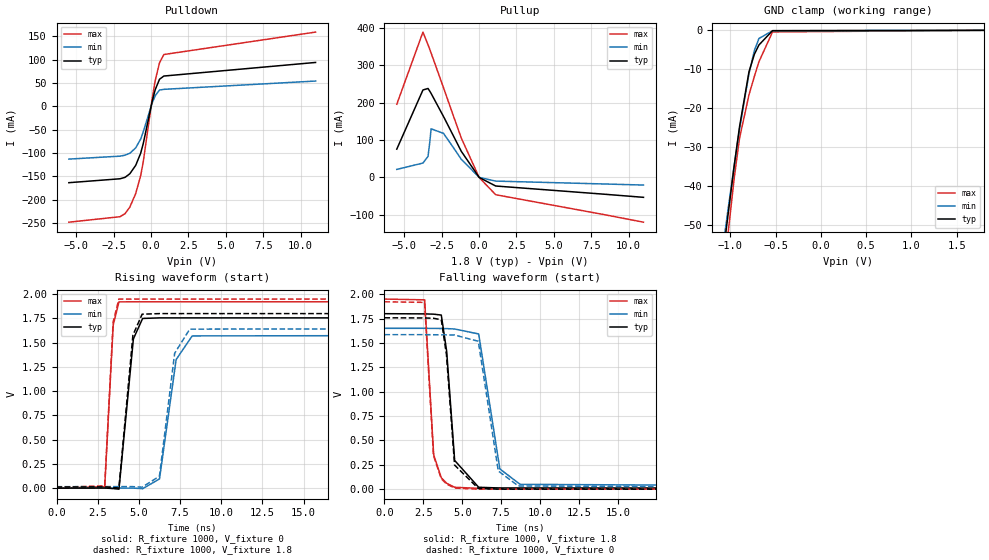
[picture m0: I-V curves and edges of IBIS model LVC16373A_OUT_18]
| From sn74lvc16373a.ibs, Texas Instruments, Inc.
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[Model]   LVC16373A_OUT_18
Model_type  3-state
Enable   Active-Low
Vref =   0
Rref =   1000
Cref =   30p
Vmeas =   0.9
| variable   typ   min   max
C_comp   5.28pF   4.71pF   6.10pF
| C_pullup   6.13pF   5.53pF   6.81pF
| C_pulldown   8.31pF   6.61pF   10.14pF
| C_tri-state   5.28pF   4.71pF   6.10pF
[Temperature Range]   40   100   -40
| Ambient temperature   25   85   -40
[Voltage range]   1.8   1.65   1.95
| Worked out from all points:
|   slope of the pulldown table from 0 to 0.27 V, typ, clamps not added: 7.65 ohm
|   slope of the pullup table from 0 to 0.27 V, typ, clamps not added: 27.4 ohm
|   GND clamp passes 1 mA (typ) near -0.60 V on its own axis
|   rising waveform, R_fixture 1000, V_fixture 0: 20-80 % time 380ps typ, 692ps min, 239ps max; typ from 0 V to 1.76 V
|   falling waveform, R_fixture 1000, V_fixture 1.8: 20-80 % time 481ps typ, 783ps min, 350ps max; typ from 1.8 V to 0.012 V
|   rising waveform, R_fixture 1000, V_fixture 1.8: 20-80 % time 366ps typ, 633ps min, 235ps max; typ from 0.012 V to 1.8 V
|   falling waveform, R_fixture 1000, V_fixture 0: 20-80 % time 467ps typ, 742ps min, 343ps max; typ from 1.76 V to 0 V
[GND Clamp]
| LVC16373A_OUT_18
|   Voltage   I(typ)   I(min)   I(max)
-5.5V     -1.092A    -985.9mA   -1.265A
-1.12V    -65.63mA   -62.5mA    -73.1mA
-1.09V    -59.68mA   -57.14mA   -66.23mA
-1.06V    -53.82mA   -51.86mA   -59.48mA
-1.045V   -50.92mA   -49.25mA   -56.15mA
-960mV    -35.13mA   -34.95mA   -38.34mA
-900mV    -24.87mA   -25.49mA   -27.8mA
-795mV    -10.66mA   -11.13mA   -16.59mA
-735mV    -6.119mA   -5.16mA    -11.82mA
-685mV    -3.765mA   -2.107mA   -8.076mA
-535mV    -84.46uA   -113.4uA   -414.9uA
1.8V      37.81pA    12.23nA    -1.85nA
[Pulldown]
| LVC16373A_OUT_18
|   Voltage   I(typ)   I(min)   I(max)
-5.5V     -163.6mA   -113mA     -248.3mA
-2.075V   -155.2mA   -106.7mA   -236.5mA
-1.745V   -152.2mA   -104.6mA   -230mA
-1.42V    -144.4mA   -100.5mA   -215.8mA
-1.03V    -126.4mA   -88.99mA   -186.9mA
-695mV    -100.2mA   -69.99mA   -148.2mA
-520mV    -79.1mA    -54.01mA   -118mA
70mV      10.47mA    6.993mA    15.91mA
275mV     35.8mA     23.13mA    55.48mA
565mV     58.22mA    35.03mA    93.73mA
855mV     65.08mA    36.56mA    111.2mA
11V       94.21mA    54.33mA    159.3mA
[Pullup]
| LVC16373A_OUT_18
|   Voltage   I(typ)   I(min)   I(max)
-5.5V     75.37mA    20.95mA    195.8mA
-3.75V    234.1mA    38.04mA    389.4mA
-3.41V    238.1mA    55.86mA    355.3mA
-3.285V   230.3mA    96.69mA    342mA
-3.205V   224.9mA    129.9mA    333.3mA
-2.375V   162.9mA    117.7mA    240.2mA
-1.61V    102.9mA    73.43mA    152.8mA
-1.185V   69.47mA    48.03mA    105.1mA
15mV      -631.9uA   -377.7uA   -1.037mA
1.115V    -23.53mA   -10.37mA   -46.86mA
8.41V     -45.64mA   -18.13mA   -100.6mA
11V       -53.91mA   -20.99mA   -120.6mA
[Ramp]
| LVC16373A_OUT_18
| variable   typ   min   max
dV/dt_r   1.06/3.92E-10   0.96/7.01E-10   1.16/2.51E-10
dV/dt_f   1.07/4.87E-10   0.98/7.88E-10   1.17/3.60E-10
R_load = 1000
[Rising Waveform]
| LVC16373A_OUT_18
R_fixture =   1000
C_fixture =   0
L_fixture =   0
V_fixture =   0
V_fixture_min = 0
V_fixture_max = 0
|   Time   V(typ)   V(min)   V(max)
0s        561.2pV    2.27nV     19.09nV
2.925ns   1.743mV    188.8uV    15.66mV
3.44ns    -3.94mV    1.332mV    1.683V
3.79ns    -10.17mV   824.7uV    1.921V
4.665ns   1.54V      696.2uV    1.922V
5.225ns   1.75V      -5.31mV    1.922V
6.25ns    1.756V     95.72mV    1.922V
7.26ns    1.756V     1.327V     1.922V
8.235ns   1.756V     1.57V      1.922V
50ns      1.756V     1.581V     1.922V
[Falling Waveform]
| LVC16373A_OUT_18
R_fixture =   1000
C_fixture =   0
L_fixture =   0
V_fixture =   1.8
V_fixture_min = 1.65
V_fixture_max = 1.95
|   Time   V(typ)   V(min)   V(max)
0s        1.8V       1.65V      1.95V
2.585ns   1.798V     1.65V      1.942V
3.165ns   1.795V     1.649V     353.4mV
3.655ns   1.786V     1.648V     117.7mV
4ns       1.416V     1.647V     60.59mV
4.515ns   294.8mV    1.643V     19.35mV
6.06ns    19.39mV    1.592V     8.507mV
7.42ns    11.92mV    207.4mV    8.37mV
8.725ns   11.61mV    49.58mV    8.362mV
50ns      11.53mV    15.73mV    8.262mV
[Rising Waveform]
| LVC16373A_OUT_18
R_fixture =   1000
C_fixture =   0
L_fixture =   0
V_fixture =   1.8
V_fixture_min = 1.65
V_fixture_max = 1.95
|   Time   V(typ)   V(min)   V(max)
0s        11.51mV    15.68mV    8.257mV
2.925ns   13.05mV    15.89mV    24.81mV
3.435ns   7.463mV    16.78mV    1.714V
3.785ns   1.792mV    16.11mV    1.95V
4.635ns   1.577V     15.89mV    1.95V
5.195ns   1.794V     10.37mV    1.95V
6.245ns   1.8V       123.5mV    1.95V
7.17ns    1.8V       1.392V     1.95V
8.085ns   1.8V       1.64V      1.95V
50ns      1.8V       1.65V      1.95V
[Falling Waveform]
| LVC16373A_OUT_18
R_fixture =   1000
C_fixture =   0
L_fixture =   0
V_fixture =   0
V_fixture_min = 0
V_fixture_max = 0
|   Time   V(typ)   V(min)   V(max)
0s        1.758V     1.585V     1.922V
2.58ns    1.756V     1.585V     1.916V
3.155ns   1.753V     1.584V     342.1mV
3.655ns   1.738V     1.583V     107.8mV
3.985ns   1.381V     1.583V     53.5mV
4.51ns    247.2mV    1.581V     11.1mV
6.035ns   7.702mV    1.517V     252uV
7.32ns    430.2uV    186.4mV    114.1uV
8.61ns    105.2uV    33.14mV    103.3uV
50ns      12.69uV    48.2uV     5.024uV
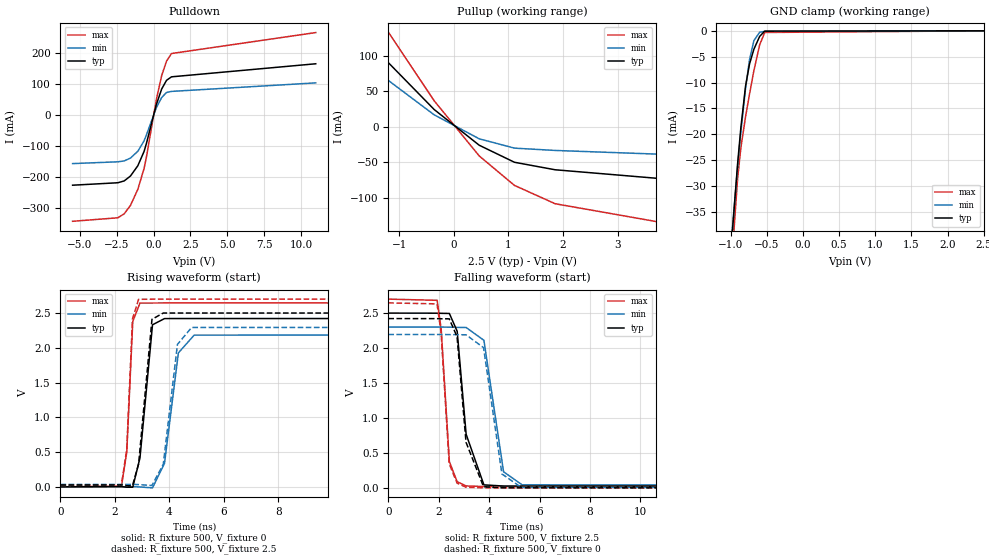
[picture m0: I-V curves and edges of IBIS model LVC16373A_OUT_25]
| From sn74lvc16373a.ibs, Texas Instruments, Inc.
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[Model]   LVC16373A_OUT_25
Model_type  3-state
Enable   Active-Low
Vref =   0
Rref =   500
Cref =   30p
Vmeas =   1.25
| variable   typ   min   max
C_comp   5.09pF   4.48pF   6.05pF
| C_pullup   6.01pF   5.36pF   6.86pF
| C_pulldown   7.61pF   6.27pF   8.94pF
| C_tri-state   5.09pF   4.48pF   6.05pF
[Temperature Range]   40   100   -40
| Ambient temperature   25   85   -40
[Voltage range]   2.5   2.3   2.7
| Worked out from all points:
|   slope of the pulldown table from 0 to 0.375 V, typ, clamps not added: 6 ohm
|   slope of the pullup table from 0 to 0.375 V, typ, clamps not added: 17.5 ohm
|   GND clamp passes 1 mA (typ) near -0.60 V on its own axis
|   rising waveform, R_fixture 500, V_fixture 0: 20-80 % time 256ps typ, 373ps min, 165ps max; typ from 0 V to 2.42 V
|   falling waveform, R_fixture 500, V_fixture 2.5: 20-80 % time 333ps typ, 469ps min, 250ps max; typ from 2.5 V to 0.025 V
|   rising waveform, R_fixture 500, V_fixture 2.5: 20-80 % time 254ps typ, 356ps min, 162ps max; typ from 0.025 V to 2.5 V
|   falling waveform, R_fixture 500, V_fixture 0: 20-80 % time 321ps typ, 441ps min, 244ps max; typ from 2.42 V to 0 V
[GND Clamp]
| LVC16373A_OUT_25
|   Voltage   I(typ)   I(min)   I(max)
-5.5V     -1.092A    -985.9mA   -1.265A
-1.115V   -64.63mA   -61.6mA    -71.95mA
-1.085V   -58.69mA   -56.25mA   -65.09mA
-1.055V   -52.85mA   -50.99mA   -58.36mA
-905mV    -25.68mA   -26.25mA   -28.57mA
-860mV    -18.71mA   -19.61mA   -22.6mA
-795mV    -10.66mA   -11.13mA   -16.59mA
-740mV    -6.406mA   -5.567mA   -12.21mA
-680mV    -3.568mA   -1.9mA     -7.713mA
-600mV    -1.079mA   -275.4uA   -2.703mA
-530mV    -59.09uA   -106.9uA   -320.1uA
2.5V      50.35pA    32nA       -2.079nA
[Pulldown]
| LVC16373A_OUT_25
|   Voltage   I(typ)   I(min)   I(max)
-5.5V     -227.2mA   -157.4mA   -343.8mA
-2.435V   -219.3mA   -151.6mA   -332.5mA
-2V       -213.4mA   -148.8mA   -319.6mA
-1.575V   -197.6mA   -139.6mA   -292.6mA
-1.075V   -164.4mA   -117.7mA   -240.6mA
-650mV    -118.1mA   -83.84mA   -173.1mA
-495mV    -93.12mA   -65.26mA   -137.4mA
185mV     33.61mA    23.27mA    50.14mA
545mV     83.64mA    56.25mA    127.2mA
875mV     111.7mA    72.29mA    173.9mA
1.21V     122.9mA    75.8mA     198.2mA
11V       165.1mA    103.4mA    265.9mA
[Pullup]
| LVC16373A_OUT_25
|   Voltage   I(typ)   I(min)   I(max)
-5.5V     443.1mA    133.6mA    676.2mA
-5.3V     442mA      146.1mA    654.8mA
-2.67V    223.9mA    166.9mA    324.6mA
-2.115V   173mA      128.2mA    251.7mA
-1.69V    134.3mA    98.74mA    196.2mA
-1.285V   97.35mA    70.47mA    143.5mA
-360mV    24.51mA    17.05mA    36.8mA
465mV     -25.84mA   -16.77mA   -40.96mA
1.11V     -49.84mA   -29.91mA   -82.48mA
1.855V    -60.43mA   -33.17mA   -108.3mA
4.49V     -77.42mA   -40.47mA   -144.1mA
11V       -121.1mA   -58.83mA   -239.8mA
[Ramp]
| LVC16373A_OUT_25
| variable   typ   min   max
dV/dt_r   1.46/2.66E-10   1.32/3.80E-10   1.60/1.70E-10
dV/dt_f   1.49/3.41E-10   1.36/4.74E-10   1.61/2.54E-10
R_load = 500
[Rising Waveform]
| LVC16373A_OUT_25
R_fixture =   500
C_fixture =   0
L_fixture =   0
V_fixture =   0
V_fixture_min = 0
V_fixture_max = 0
|   Time   V(typ)   V(min)   V(max)
0s        617.4pV    1.958nV    18.26nV
2.24ns    2.519mV    383.6uV    8.954mV
2.435ns   -6.245mV   2.016mV    499.9mV
2.655ns   -5.407mV   2.679mV    2.378V
2.92ns    416.1mV    -2.426mV   2.644V
3.38ns    2.331V     -15.13mV   2.644V
3.82ns    2.42V      337mV      2.645V
4.33ns    2.421V     1.927V     2.645V
4.91ns    2.421V     2.182V     2.645V
50ns      2.421V     2.191V     2.645V
[Falling Waveform]
| LVC16373A_OUT_25
R_fixture =   500
C_fixture =   0
L_fixture =   0
V_fixture =   2.5
V_fixture_min = 2.3
V_fixture_max = 2.7
|   Time   V(typ)   V(min)   V(max)
0s        2.5V       2.3V       2.7V
1.935ns   2.499V     2.3V       2.683V
2.095ns   2.497V     2.3V       2.269V
2.42ns    2.495V     2.299V     374.2mV
2.73ns    2.24V      2.296V     87.5mV
3.085ns   766.4mV    2.294V     27.43mV
3.79ns    42.52mV    2.111V     19.07mV
4.57ns    26.27mV    230.1mV    18.74mV
5.305ns   25.66mV    43.14mV    18.68mV
50ns      25.46mV    33.49mV    18.58mV
[Rising Waveform]
| LVC16373A_OUT_25
R_fixture =   500
C_fixture =   0
L_fixture =   0
V_fixture =   2.5
V_fixture_min = 2.3
V_fixture_max = 2.7
|   Time   V(typ)   V(min)   V(max)
0s        25.45mV    33.45mV    18.57mV
2.24ns    27.69mV    33.83mV    28.34mV
2.435ns   18.91mV    35.28mV    543.1mV
2.645ns   17.43mV    35.61mV    2.416V
2.87ns    328.7mV    31.4mV     2.697V
3.36ns    2.41V      19.15mV    2.699V
3.775ns   2.5V       324.7mV    2.7V
4.295ns   2.5V       2.048V     2.7V
4.815ns   2.5V       2.292V     2.7V
50ns      2.5V       2.3V       2.7V
[Falling Waveform]
| LVC16373A_OUT_25
R_fixture =   500
C_fixture =   0
L_fixture =   0
V_fixture =   0
V_fixture_min = 0
V_fixture_max = 0
|   Time   V(typ)   V(min)   V(max)
0s        2.422V     2.194V     2.646V
1.93ns    2.421V     2.194V     2.632V
2.09ns    2.419V     2.194V     2.23V
2.415ns   2.418V     2.192V     342.2mV
2.725ns   2.162V     2.191V     67.56mV
3.08ns    652.7mV    2.19V      8.625mV
3.775ns   16.27mV    2.006V     485.8uV
4.505ns   810.4uV    198.7mV    178.5uV
5.265ns   206.8uV    8.456mV    105.8uV
50ns      9.942uV    37.37uV    3.898uV
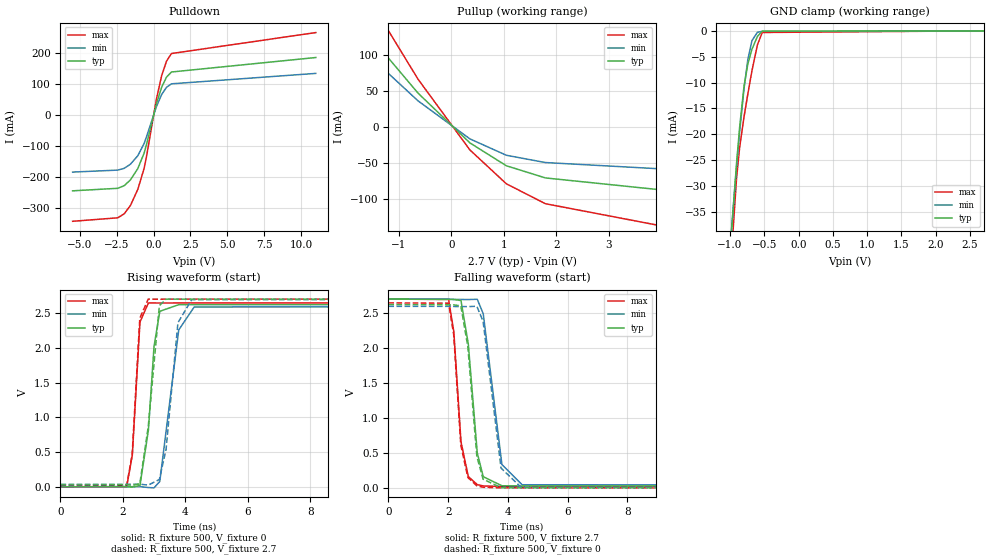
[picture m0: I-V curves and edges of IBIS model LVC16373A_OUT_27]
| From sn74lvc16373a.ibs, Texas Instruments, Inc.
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[Model]   LVC16373A_OUT_27
Model_type  3-state
Enable   Active-Low
Vref =   0
Rref =   500
Cref =   50p
Vmeas =   1.5
| variable   typ   min   max
C_comp   5.04pF   4.40pF   6.03pF
| C_pullup   5.98pF   5.29pF   6.85pF
| C_pulldown   7.47pF   6.10pF   8.69pF
| C_tri-state   5.04pF   4.40pF   6.03pF
[Temperature Range]   40   100   -40
| Ambient temperature   25   85   -40
[Voltage range]   2.7   2.7   2.7
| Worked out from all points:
|   slope of the pulldown table from 0 to 0.405 V, typ, clamps not added: 5.72 ohm
|   slope of the pullup table from 0 to 0.405 V, typ, clamps not added: 16.1 ohm
|   GND clamp passes 1 mA (typ) near -0.60 V on its own axis
|   rising waveform, R_fixture 500, V_fixture 0: 20-80 % time 245ps typ, 318ps min, 183ps max; typ from 0 V to 2.62 V
|   falling waveform, R_fixture 500, V_fixture 2.7: 20-80 % time 311ps typ, 396ps min, 247ps max; typ from 2.7 V to 0.026 V
|   rising waveform, R_fixture 500, V_fixture 2.7: 20-80 % time 238ps typ, 307ps min, 180ps max; typ from 0.026 V to 2.7 V
|   falling waveform, R_fixture 500, V_fixture 0: 20-80 % time 300ps typ, 376ps min, 242ps max; typ from 2.62 V to 0 V
[GND Clamp]
| LVC16373A_OUT_27
|   Voltage   I(typ)   I(min)   I(max)
-5.5V     -1.092A    -985.9mA   -1.265A
-1.115V   -64.63mA   -61.6mA    -71.95mA
-1.085V   -58.69mA   -56.25mA   -65.09mA
-1.055V   -52.85mA   -50.99mA   -58.36mA
-905mV    -25.68mA   -26.25mA   -28.57mA
-860mV    -18.71mA   -19.61mA   -22.6mA
-795mV    -10.66mA   -11.13mA   -16.59mA
-740mV    -6.406mA   -5.567mA   -12.21mA
-680mV    -3.568mA   -1.9mA     -7.713mA
-600mV    -1.079mA   -275.4uA   -2.703mA
-530mV    -59.09uA   -106.9uA   -320.1uA
2.7V      53.94pA    179.8pA    444.4pA
[Pulldown]
| LVC16373A_OUT_27
|   Voltage   I(typ)   I(min)   I(max)
-5.5V     -245.4mA   -184.8mA   -343.8mA
-2.435V   -237.2mA   -178.4mA   -332.5mA
-2V       -228.7mA   -172.7mA   -319.6mA
-1.575V   -210.1mA   -159.3mA   -292.6mA
-1.075V   -173.4mA   -131.9mA   -240.6mA
-650mV    -123.8mA   -92.78mA   -173.1mA
-495mV    -97.47mA   -72.18mA   -137.4mA
185mV     35.44mA    26.23mA    50.14mA
545mV     89.62mA    65.99mA    127.2mA
875mV     122.2mA    89.37mA    173.9mA
1.21V     138.5mA    100.3mA    198.2mA
11V       185.3mA    134mA      265.9mA
[Pullup]
| LVC16373A_OUT_27
|   Voltage   I(typ)   I(min)   I(max)
-5.5V     483.8mA    373.3mA    676.2mA
-2.955V   260.4mA    204.9mA    362.1mA
-2.39V    206.7mA    162.3mA    287.8mA
-1.905V   160.8mA    125.9mA    224.3mA
-1.51V    123.7mA    96.36mA    172.5mA
-1.42V    115.2mA    89.57mA    160.8mA
-635mV    47.2mA     36.42mA    66.66mA
355mV     -22.29mA   -16.67mA   -32.11mA
1.05V     -54.18mA   -39.53mA   -79.36mA
1.795V    -71.14mA   -49.69mA   -107.1mA
6.11V     -103.7mA   -66.95mA   -167.5mA
11V       -142.2mA   -87.05mA   -239.8mA
[Ramp]
| LVC16373A_OUT_27
| variable   typ   min   max
dV/dt_r   1.58/2.56E-10   1.57/3.25E-10   1.59/1.89E-10
dV/dt_f   1.60/3.19E-10   1.60/4.04E-10   1.61/2.48E-10
R_load = 500
[Rising Waveform]
| LVC16373A_OUT_27
R_fixture =   500
C_fixture =   0
L_fixture =   0
V_fixture =   0
V_fixture_min = 0
V_fixture_max = 0
|   Time   V(typ)   V(min)   V(max)
0s        636.7pV    1.895nV    18.26nV
2.12ns    2.759mV    305uV      547.3uV
2.3ns     -5.789mV   2.063mV    454.9mV
2.545ns   19.38mV    1.984mV    2.371V
2.815ns   815mV      -10.88mV   2.645V
2.995ns   2.021V     -15.51mV   2.645V
3.18ns    2.525V     77.27mV    2.644V
3.785ns   2.62V      2.256V     2.645V
4.28ns    2.621V     2.587V     2.645V
50ns      2.621V     2.595V     2.645V
[Falling Waveform]
| LVC16373A_OUT_27
R_fixture =   500
C_fixture =   0
L_fixture =   0
V_fixture =   2.7
V_fixture_min = 2.7
V_fixture_max = 2.7
|   Time   V(typ)   V(min)   V(max)
0s        2.7V       2.7V       2.7V
2.015ns   2.696V     2.7V       2.696V
2.19ns    2.694V     2.697V     2.235V
2.43ns    2.68V      2.695V     659.1mV
2.675ns   2.058V     2.694V     161.5mV
2.975ns   499.4mV    2.698V     46.57mV
3.175ns   159.7mV    2.49V      27.32mV
3.8ns     30.02mV    333.6mV    19.13mV
4.475ns   26.8mV     44.36mV    18.78mV
50ns      26.24mV    35.41mV    18.58mV
[Rising Waveform]
| LVC16373A_OUT_27
R_fixture =   500
C_fixture =   0
L_fixture =   0
V_fixture =   2.7
V_fixture_min = 2.7
V_fixture_max = 2.7
|   Time   V(typ)   V(min)   V(max)
0s        26.23mV    35.37mV    18.57mV
2.12ns    28.76mV    35.68mV    19.76mV
2.295ns   20.63mV    37.23mV    464.1mV
2.54ns    43.52mV    36.93mV    2.427V
2.81ns    866.7mV    24.46mV    2.7V
3.165ns   2.605V     104.5mV    2.699V
3.38ns    2.7V       537.3mV    2.7V
3.76ns    2.7V       2.361V     2.7V
4.2ns     2.7V       2.692V     2.7V
50ns      2.7V       2.7V       2.7V
[Falling Waveform]
| LVC16373A_OUT_27
R_fixture =   500
C_fixture =   0
L_fixture =   0
V_fixture =   0
V_fixture_min = 0
V_fixture_max = 0
|   Time   V(typ)   V(min)   V(max)
0s        2.622V     2.597V     2.646V
2.015ns   2.619V     2.597V     2.642V
2.185ns   2.617V     2.595V     2.196V
2.425ns   2.604V     2.593V     608.9mV
2.66ns    2.016V     2.593V     148.2mV
2.96ns    450.1mV    2.598V     29.16mV
3.17ns    123.7mV    2.382V     8.526mV
3.77ns    3.773mV    283mV      566.6uV
4.44ns    534uV      8.356mV    209uV
50ns      9.764uV    37.63uV    3.912uV
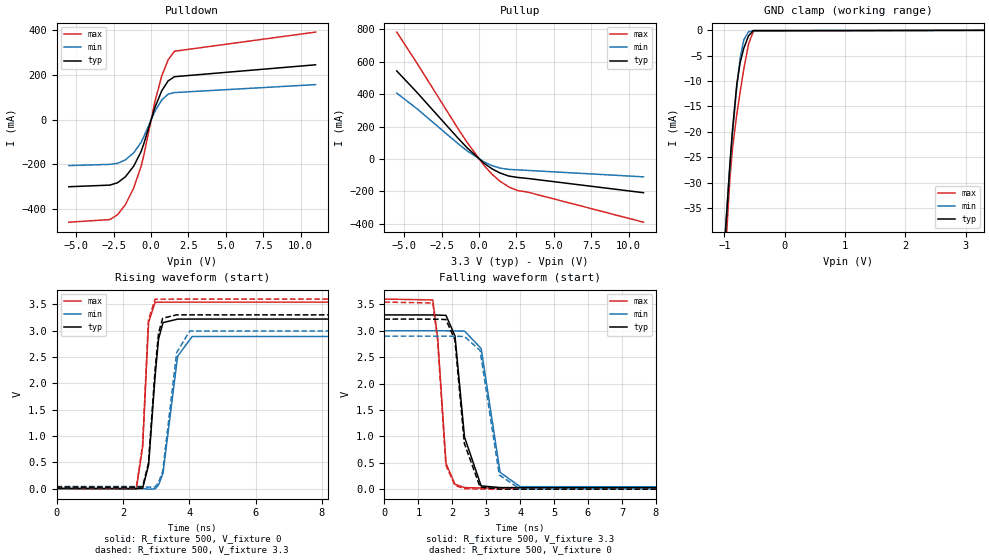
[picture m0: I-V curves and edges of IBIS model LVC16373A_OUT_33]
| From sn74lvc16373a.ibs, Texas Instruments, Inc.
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[Model]   LVC16373A_OUT_33
Model_type  3-state
Enable   Active-Low
Vref =   0
Rref =   500
Cref =   50p
Vmeas =   1.5
| variable   typ   min   max
C_comp   4.92pF   4.28pF   6.02pF
| C_pullup   5.95pF   5.18pF   6.99pF
| C_pulldown   7.16pF   5.94pF   8.13pF
| C_tri-state   4.92pF   4.28pF   6.02pF
[Temperature Range]   40   100   -40
| Ambient temperature   25   85   -40
[Voltage range]   3.3   3   3.6
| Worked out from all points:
|   slope of the pulldown table from 0 to 0.495 V, typ, clamps not added: 5.09 ohm
|   slope of the pullup table from 0 to 0.495 V, typ, clamps not added: 13.3 ohm
|   GND clamp passes 1 mA (typ) near -0.60 V on its own axis
|   rising waveform, R_fixture 500, V_fixture 0: 20-80 % time 214ps typ, 293ps min, 155ps max; typ from 0 V to 3.22 V
|   falling waveform, R_fixture 500, V_fixture 3.3: 20-80 % time 268ps typ, 364ps min, 203ps max; typ from 3.3 V to 0.029 V
|   rising waveform, R_fixture 500, V_fixture 3.3: 20-80 % time 211ps typ, 285ps min, 153ps max; typ from 0.029 V to 3.3 V
|   falling waveform, R_fixture 500, V_fixture 0: 20-80 % time 260ps typ, 347ps min, 199ps max; typ from 3.22 V to 0 V
[GND Clamp]
| LVC16373A_OUT_33
|   Voltage   I(typ)   I(min)   I(max)
-5.5V     -1.092A    -985.9mA   -1.265A
-1.13V    -67.63mA   -64.3mA    -75.42mA
-1.095V   -60.66mA   -58.03mA   -67.37mA
-1.065V   -54.79mA   -52.74mA   -60.59mA
-910mV    -26.51mA   -27.02mA   -29.36mA
-865mV    -19.44mA   -20.32mA   -23.16mA
-795mV    -10.66mA   -11.13mA   -16.59mA
-740mV    -6.406mA   -5.567mA   -12.21mA
-680mV    -3.568mA   -1.9mA     -7.713mA
-600mV    -1.079mA   -275.4uA   -2.703mA
-520mV    -35.47uA   -95.17uA   -168.9uA
3.3V      64.68pA    54.59nA    -2.347nA
[Pulldown]
| LVC16373A_OUT_33
|   Voltage   I(typ)   I(min)   I(max)
-5.5V     -300mA     -205.4mA   -458.6mA
-2.76V    -292.7mA   -199.9mA   -447mA
-2.24V    -282mA     -195.3mA   -425mA
-1.72V    -255.5mA   -179.7mA   -380.4mA
-1.16V    -207.6mA   -148.1mA   -305.1mA
-670mV    -142.6mA   -101.5mA   -209.1mA
-500mV    -110.4mA   -77.62mA   -163.1mA
255mV     54.31mA    37.86mA    80.86mA
710mV     129mA      87.77mA    195.2mA
1.135V    173mA      114mA      267.3mA
1.56V     192.2mA    121.2mA    306.1mA
11V       245.5mA    156.8mA    391.8mA
[Pullup]
| LVC16373A_OUT_33
|   Voltage   I(typ)   I(min)   I(max)
-5.5V     543.3mA    406.3mA    783.2mA
-4.16V    412.1mA    311.1mA    592.9mA
-1.405V   128.8mA    95.07mA    187.7mA
-805mV    70.25mA    51.09mA    103.8mA
370mV     -28.42mA   -19.63mA   -43.35mA
890mV     -61.47mA   -41.24mA   -95.52mA
1.405V    -86.3mA    -55.79mA   -137.1mA
1.995V    -105.1mA   -64.06mA   -172.4mA
2.59V     -113.6mA   -66.71mA   -194.7mA
3.25V     -119.7mA   -70.05mA   -203.9mA
11V       -207.7mA   -109.8mA   -389.6mA
[Ramp]
| LVC16373A_OUT_33
| variable   typ   min   max
dV/dt_r   1.94/2.20E-10   1.75/3.08E-10   2.13/1.57E-10
dV/dt_f   1.96/2.74E-10   1.78/3.69E-10   2.15/2.07E-10
R_load = 500
[Rising Waveform]
| LVC16373A_OUT_33
R_fixture =   500
C_fixture =   0
L_fixture =   0
V_fixture =   0
V_fixture_min = 0
V_fixture_max = 0
|   Time   V(typ)   V(min)   V(max)
0s        794.3pV    1.869nV    18.83nV
2.405ns   -3.272mV   2.974mV    -7.658mV
2.595ns   2.436mV    -57.83uV   790.3mV
2.775ns   449.6mV    -12.54mV   3.16V
2.97ns    2.127V     -7.908mV   3.538V
3.075ns   2.842V     67.42mV    3.54V
3.21ns    3.153V     292.5mV    3.541V
3.65ns    3.219V     2.514V     3.542V
4.09ns    3.22V      2.889V     3.542V
50ns      3.22V      2.895V     3.542V
[Falling Waveform]
| LVC16373A_OUT_33
R_fixture =   500
C_fixture =   0
L_fixture =   0
V_fixture =   3.3
V_fixture_min = 3
V_fixture_max = 3.6
|   Time   V(typ)   V(min)   V(max)
0s        3.3V       3V         3.6V
1.425ns   3.299V     3V         3.583V
1.57ns    3.297V     3V         2.858V
1.815ns   3.291V     2.999V     485mV
2.08ns    2.901V     2.995V     92.83mV
2.36ns    986.3mV    2.993V     30.95mV
2.85ns    62.3mV     2.665V     21.9mV
3.41ns    29.98mV    317.3mV    21.34mV
4ns       28.9mV     46.78mV    21.24mV
50ns      28.59mV    36.92mV    21.11mV
[Rising Waveform]
| LVC16373A_OUT_33
R_fixture =   500
C_fixture =   0
L_fixture =   0
V_fixture =   3.3
V_fixture_min = 3
V_fixture_max = 3.6
|   Time   V(typ)   V(min)   V(max)
0s        28.58mV    36.89mV    21.11mV
2.405ns   25.04mV    39.63mV    13.77mV
2.595ns   32.28mV    36.19mV    838.1mV
2.77ns    479.1mV    24.4mV     3.206V
2.97ns    2.251V     30.96mV    3.597V
3.075ns   2.955V     110.4mV    3.598V
3.2ns     3.236V     328.9mV    3.598V
3.62ns    3.3V       2.582V     3.6V
4.015ns   3.3V       2.993V     3.6V
50ns      3.3V       3V         3.6V
[Falling Waveform]
| LVC16373A_OUT_33
R_fixture =   500
C_fixture =   0
L_fixture =   0
V_fixture =   0
V_fixture_min = 0
V_fixture_max = 0
|   Time   V(typ)   V(min)   V(max)
0s        3.221V     2.898V     3.543V
1.425ns   3.22V      2.898V     3.525V
1.565ns   3.218V     2.898V     2.83V
1.81ns    3.213V     2.897V     456.9mV
2.075ns   2.833V     2.894V     71.86mV
2.355ns   868mV      2.893V     9.747mV
2.82ns    37.47mV    2.626V     838.9uV
3.385ns   1.313mV    268.7mV    236.2uV
3.985ns   293.8uV    8.54mV     128.7uV
50ns      9.734uV    37.62uV    3.439uV
